One B-rep face of a CAD part: STEP entity #73938.
In plain terms, the planar face has unit normal (0, 0, 1).
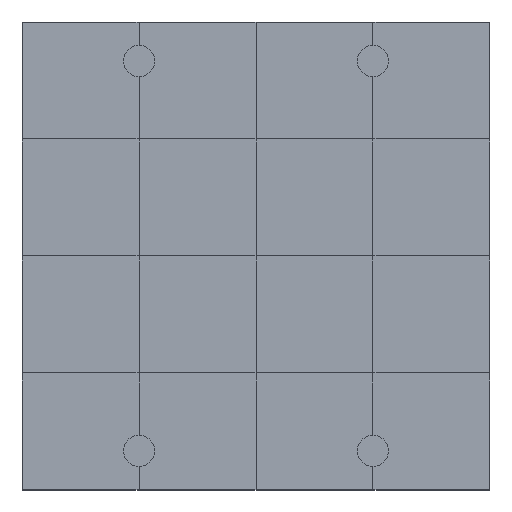
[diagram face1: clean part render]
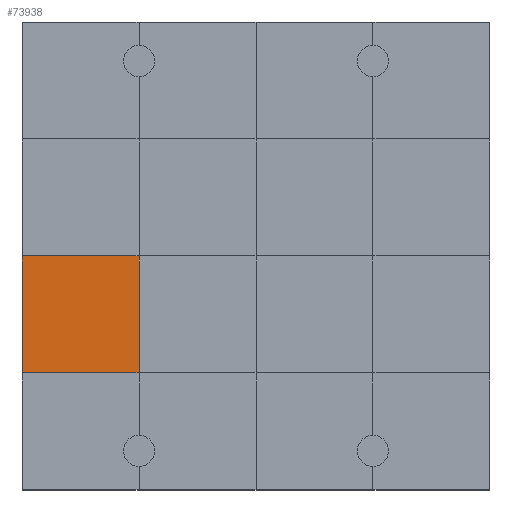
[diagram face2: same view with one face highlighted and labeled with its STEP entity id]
Its self-contained STEP definition (entity closure, numbers rounded to 3 decimals):
#73488 = VERTEX_POINT('',#73489);
#73489 = CARTESIAN_POINT('',(0.,3.,1.2));
#73503 = PLANE('',#73504);
#73504 = AXIS2_PLACEMENT_3D('',#73505,#73506,#73507);
#73505 = CARTESIAN_POINT('',(0.,3.,0.));
#73506 = DIRECTION('',(1.,0.,-0.));
#73507 = DIRECTION('',(0.,0.,1.));
#73529 = PLANE('',#73530);
#73530 = AXIS2_PLACEMENT_3D('',#73531,#73532,#73533);
#73531 = CARTESIAN_POINT('',(0.,0.,1.2));
#73532 = DIRECTION('',(0.,0.,1.));
#73533 = DIRECTION('',(1.,0.,-0.));
#73680 = VERTEX_POINT('',#73681);
#73681 = CARTESIAN_POINT('',(3.,3.,1.2));
#73702 = EDGE_CURVE('',#73488,#73680,#73703,.T.);
#73703 = SURFACE_CURVE('',#73704,(#73708,#73715),.PCURVE_S1.);
#73704 = LINE('',#73705,#73706);
#73705 = CARTESIAN_POINT('',(0.,3.,1.2));
#73706 = VECTOR('',#73707,1.);
#73707 = DIRECTION('',(1.,0.,-0.));
#73708 = PCURVE('',#73529,#73709);
#73709 = DEFINITIONAL_REPRESENTATION('',(#73710),#73714);
#73710 = LINE('',#73711,#73712);
#73711 = CARTESIAN_POINT('',(0.,3.));
#73712 = VECTOR('',#73713,1.);
#73713 = DIRECTION('',(1.,0.));
#73714 = ( GEOMETRIC_REPRESENTATION_CONTEXT(2) 
PARAMETRIC_REPRESENTATION_CONTEXT() REPRESENTATION_CONTEXT('2D SPACE',''
  ) );
#73715 = PCURVE('',#73716,#73721);
#73716 = PLANE('',#73717);
#73717 = AXIS2_PLACEMENT_3D('',#73718,#73719,#73720);
#73718 = CARTESIAN_POINT('',(0.,3.,1.2));
#73719 = DIRECTION('',(0.,0.,1.));
#73720 = DIRECTION('',(1.,0.,-0.));
#73721 = DEFINITIONAL_REPRESENTATION('',(#73722),#73726);
#73722 = LINE('',#73723,#73724);
#73723 = CARTESIAN_POINT('',(0.,0.));
#73724 = VECTOR('',#73725,1.);
#73725 = DIRECTION('',(1.,0.));
#73726 = ( GEOMETRIC_REPRESENTATION_CONTEXT(2) 
PARAMETRIC_REPRESENTATION_CONTEXT() REPRESENTATION_CONTEXT('2D SPACE',''
  ) );
#73761 = VERTEX_POINT('',#73762);
#73762 = CARTESIAN_POINT('',(0.,6.,1.2));
#73788 = EDGE_CURVE('',#73488,#73761,#73789,.T.);
#73789 = SURFACE_CURVE('',#73790,(#73794,#73801),.PCURVE_S1.);
#73790 = LINE('',#73791,#73792);
#73791 = CARTESIAN_POINT('',(0.,3.,1.2));
#73792 = VECTOR('',#73793,1.);
#73793 = DIRECTION('',(-0.,1.,0.));
#73794 = PCURVE('',#73503,#73795);
#73795 = DEFINITIONAL_REPRESENTATION('',(#73796),#73800);
#73796 = LINE('',#73797,#73798);
#73797 = CARTESIAN_POINT('',(1.2,0.));
#73798 = VECTOR('',#73799,1.);
#73799 = DIRECTION('',(0.,-1.));
#73800 = ( GEOMETRIC_REPRESENTATION_CONTEXT(2) 
PARAMETRIC_REPRESENTATION_CONTEXT() REPRESENTATION_CONTEXT('2D SPACE',''
  ) );
#73801 = PCURVE('',#73716,#73802);
#73802 = DEFINITIONAL_REPRESENTATION('',(#73803),#73807);
#73803 = LINE('',#73804,#73805);
#73804 = CARTESIAN_POINT('',(0.,0.));
#73805 = VECTOR('',#73806,1.);
#73806 = DIRECTION('',(0.,1.));
#73807 = ( GEOMETRIC_REPRESENTATION_CONTEXT(2) 
PARAMETRIC_REPRESENTATION_CONTEXT() REPRESENTATION_CONTEXT('2D SPACE',''
  ) );
#73938 = ADVANCED_FACE('',(#73939),#73716,.T.);
#73939 = FACE_BOUND('',#73940,.T.);
#73940 = EDGE_LOOP('',(#73941,#73942,#73943,#73971));
#73941 = ORIENTED_EDGE('',*,*,#73788,.F.);
#73942 = ORIENTED_EDGE('',*,*,#73702,.T.);
#73943 = ORIENTED_EDGE('',*,*,#73944,.T.);
#73944 = EDGE_CURVE('',#73680,#73945,#73947,.T.);
#73945 = VERTEX_POINT('',#73946);
#73946 = CARTESIAN_POINT('',(3.,6.,1.2));
#73947 = SURFACE_CURVE('',#73948,(#73952,#73959),.PCURVE_S1.);
#73948 = LINE('',#73949,#73950);
#73949 = CARTESIAN_POINT('',(3.,3.,1.2));
#73950 = VECTOR('',#73951,1.);
#73951 = DIRECTION('',(-0.,1.,0.));
#73952 = PCURVE('',#73716,#73953);
#73953 = DEFINITIONAL_REPRESENTATION('',(#73954),#73958);
#73954 = LINE('',#73955,#73956);
#73955 = CARTESIAN_POINT('',(3.,0.));
#73956 = VECTOR('',#73957,1.);
#73957 = DIRECTION('',(0.,1.));
#73958 = ( GEOMETRIC_REPRESENTATION_CONTEXT(2) 
PARAMETRIC_REPRESENTATION_CONTEXT() REPRESENTATION_CONTEXT('2D SPACE',''
  ) );
#73959 = PCURVE('',#73960,#73965);
#73960 = PLANE('',#73961);
#73961 = AXIS2_PLACEMENT_3D('',#73962,#73963,#73964);
#73962 = CARTESIAN_POINT('',(3.,3.,1.2));
#73963 = DIRECTION('',(0.,0.,1.));
#73964 = DIRECTION('',(1.,0.,-0.));
#73965 = DEFINITIONAL_REPRESENTATION('',(#73966),#73970);
#73966 = LINE('',#73967,#73968);
#73967 = CARTESIAN_POINT('',(0.,0.));
#73968 = VECTOR('',#73969,1.);
#73969 = DIRECTION('',(0.,1.));
#73970 = ( GEOMETRIC_REPRESENTATION_CONTEXT(2) 
PARAMETRIC_REPRESENTATION_CONTEXT() REPRESENTATION_CONTEXT('2D SPACE',''
  ) );
#73971 = ORIENTED_EDGE('',*,*,#73972,.F.);
#73972 = EDGE_CURVE('',#73761,#73945,#73973,.T.);
#73973 = SURFACE_CURVE('',#73974,(#73978,#73985),.PCURVE_S1.);
#73974 = LINE('',#73975,#73976);
#73975 = CARTESIAN_POINT('',(0.,6.,1.2));
#73976 = VECTOR('',#73977,1.);
#73977 = DIRECTION('',(1.,0.,-0.));
#73978 = PCURVE('',#73716,#73979);
#73979 = DEFINITIONAL_REPRESENTATION('',(#73980),#73984);
#73980 = LINE('',#73981,#73982);
#73981 = CARTESIAN_POINT('',(0.,3.));
#73982 = VECTOR('',#73983,1.);
#73983 = DIRECTION('',(1.,0.));
#73984 = ( GEOMETRIC_REPRESENTATION_CONTEXT(2) 
PARAMETRIC_REPRESENTATION_CONTEXT() REPRESENTATION_CONTEXT('2D SPACE',''
  ) );
#73985 = PCURVE('',#73986,#73991);
#73986 = PLANE('',#73987);
#73987 = AXIS2_PLACEMENT_3D('',#73988,#73989,#73990);
#73988 = CARTESIAN_POINT('',(0.,6.,1.2));
#73989 = DIRECTION('',(0.,0.,1.));
#73990 = DIRECTION('',(1.,0.,-0.));
#73991 = DEFINITIONAL_REPRESENTATION('',(#73992),#73996);
#73992 = LINE('',#73993,#73994);
#73993 = CARTESIAN_POINT('',(0.,0.));
#73994 = VECTOR('',#73995,1.);
#73995 = DIRECTION('',(1.,0.));
#73996 = ( GEOMETRIC_REPRESENTATION_CONTEXT(2) 
PARAMETRIC_REPRESENTATION_CONTEXT() REPRESENTATION_CONTEXT('2D SPACE',''
  ) );
